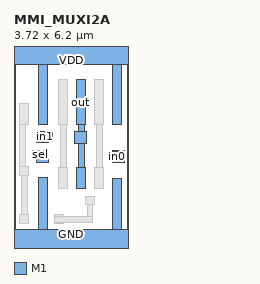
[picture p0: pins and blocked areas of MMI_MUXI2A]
MACRO MMI_MUXI2A
	CLASS CORE ;
	FOREIGN MMI_MUXI2A 0 0 ;
	SIZE 3.72 BY 6.2 ;
	SYMMETRY X Y ;
	SITE CORE1 ;
	PIN out
		DIRECTION output ;
		USE SIGNAL ;
		PORT
			LAYER M1 ;
			RECT 2.045 3.82 2.325 5.29 ;
			LAYER M1 ;
			RECT 2.09 3.6 2.285 3.82 ;
			LAYER M1 ;
			RECT 1.98 3.22 2.36 3.6 ;
			LAYER M1 ;
			RECT 2.09 2.44 2.285 3.22 ;
			LAYER M1 ;
			RECT 2.045 1.74 2.325 2.44 ;
		END
		AntennaDiffArea 1.0164 ;
	END out
	PIN sel
		DIRECTION input ;
		USE SIGNAL ;
		PORT
			LAYER M1 ;
			RECT 0.595 2.98 0.875 2.99 ;
			LAYER M1 ;
			RECT 0.595 2.71 1.12 2.98 ;
			LAYER M1 ;
			RECT 0.74 2.6 1.12 2.71 ;
		END
		AntennaGateArea 0.51975 ;
	END sel
	PIN in1
		DIRECTION input ;
		USE SIGNAL ;
		PORT
			LAYER M1 ;
			RECT 0.745 3.57 1.125 3.615 ;
			LAYER M1 ;
			RECT 0.745 3.29 1.25 3.57 ;
			LAYER M1 ;
			RECT 0.745 3.24 1.125 3.29 ;
		END
		AntennaGateArea 0.34575 ;
	END in1
	PIN GND
		DIRECTION inout ;
		USE GROUND ;
		PORT
			LAYER M1 ;
			RECT 0.815 0.42 1.095 2.115 ;
			LAYER M1 ;
			RECT 3.225 0.42 3.505 2.065 ;
			LAYER M1 ;
			RECT 0 -0.42 3.72 0.42 ;
		END
	END GND
	PIN VDD
		DIRECTION inout ;
		USE POWER ;
		PORT
			LAYER M1 ;
			RECT 0 5.78 3.72 6.62 ;
			LAYER M1 ;
			RECT 0.815 3.82 1.095 5.78 ;
			LAYER M1 ;
			RECT 3.225 3.82 3.505 5.78 ;
		END
	END VDD
	PIN in0
		DIRECTION input ;
		USE SIGNAL ;
		PORT
			LAYER M1 ;
			RECT 3.22 2.94 3.6 2.985 ;
			LAYER M1 ;
			RECT 3.135 2.66 3.6 2.94 ;
			LAYER M1 ;
			RECT 3.22 2.61 3.6 2.66 ;
		END
		AntennaGateArea 0.3465 ;
	END in0
	OBS
		LAYER M1 ;
		RECT 0.18 3.82 0.46 4.52 ;
		LAYER M1 ;
		RECT 1.455 3.82 1.735 5.29 ;
		LAYER M1 ;
		RECT 2.635 3.82 2.915 5.29 ;
		LAYER M1 ;
		RECT 0.18 2.47 0.375 3.82 ;
		LAYER M1 ;
		RECT 0.18 2.155 0.46 2.47 ;
		LAYER M1 ;
		RECT 1.51 2.44 1.7 3.82 ;
		LAYER M1 ;
		RECT 2.69 2.44 2.88 3.82 ;
		LAYER M1 ;
		RECT 0.23 0.9 0.425 2.155 ;
		LAYER M1 ;
		RECT 0.19 0.62 0.47 0.9 ;
		LAYER M1 ;
		RECT 1.455 1.74 1.735 2.44 ;
		LAYER M1 ;
		RECT 2.635 1.74 2.915 2.44 ;
		LAYER M1 ;
		RECT 2.335 1.22 2.615 1.5 ;
		LAYER M1 ;
		RECT 1.325 0.835 1.605 0.9 ;
		LAYER M1 ;
		RECT 2.385 0.835 2.575 1.22 ;
		LAYER M1 ;
		RECT 1.325 0.64 2.575 0.835 ;
		LAYER M1 ;
		RECT 1.325 0.62 1.605 0.64 ;
	END
END MMI_MUXI2A
